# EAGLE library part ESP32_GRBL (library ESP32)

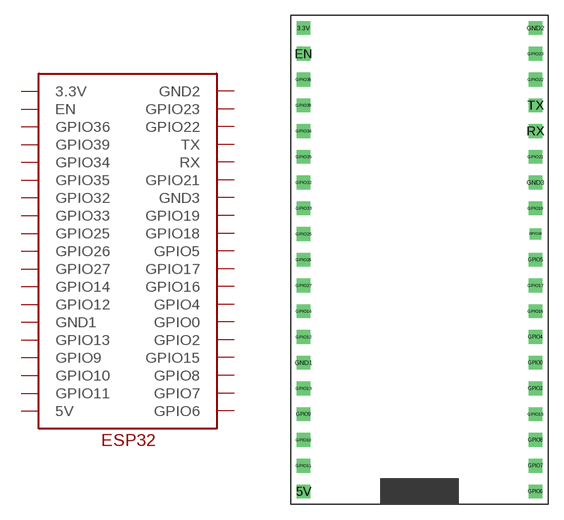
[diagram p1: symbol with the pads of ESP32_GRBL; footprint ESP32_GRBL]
Designator prefix -

## ESP32_GRBL  [ESP32_GRBL]
3.3V  3.3V
5V  5V
EN  EN
GND1  GND1
GND2  GND2
GND3  GND3
GPIO0  GPIO0
GPIO2  GPIO2
GPIO4  GPIO4
GPIO5  GPIO5
GPIO6  GPIO6
GPIO7  GPIO7
GPIO8  GPIO8
GPIO9  GPIO9
GPIO10  GPIO10
GPIO11  GPIO11
GPIO12  GPIO12
GPIO13  GPIO13
GPIO14  GPIO14
GPIO15  GPIO15
GPIO16  GPIO16
GPIO17  GPIO17
GPIO18  GPIO18
GPIO19  GPIO19
GPIO21  GPIO21
GPIO22  GPIO22
GPIO23  GPIO23
GPIO25  GPIO25
GPIO26  GPIO26
GPIO27  GPIO27
GPIO32  GPIO32
GPIO33  GPIO33
GPIO34  GPIO34
GPIO35  GPIO35
GPIO36  GPIO36
GPIO39  GPIO39
RX  RX
TX  TX

## Footprint ESP32_GRBL (pad centres in mm)
drill 0.85 square: 3.3V 1.27,46.99; 5V 1.27,1.27; EN 1.27,44.45; GND1 1.27,13.97; GND2 24.13,46.99; GND3 24.13,31.75; GPIO0 24.13,13.97; GPIO2 24.13,11.43; GPIO4 24.13,16.51; GPIO5 24.13,24.13; GPIO6 24.13,1.27; GPIO7 24.13,3.81; GPIO8 24.13,6.35; GPIO9 1.27,8.89; GPIO10 1.27,6.35; GPIO11 1.27,3.81; GPIO12 1.27,16.51; GPIO13 1.27,11.43; GPIO14 1.27,19.05; GPIO15 24.13,8.89; GPIO16 24.13,19.05; GPIO17 24.13,21.59; GPIO19 24.13,29.21; GPIO21 24.13,34.29; GPIO22 24.13,41.91; GPIO23 24.13,44.45; GPIO25 1.27,26.67; GPIO26 1.27,24.13; GPIO27 1.27,21.59; GPIO32 1.27,31.75; GPIO33 1.27,29.21; GPIO34 1.27,36.83; GPIO35 1.27,34.29; GPIO36 1.27,41.91; GPIO39 1.27,39.37; RX 24.13,36.83; TX 24.13,39.37
drill 0.6 square: GPIO18 24.13,26.67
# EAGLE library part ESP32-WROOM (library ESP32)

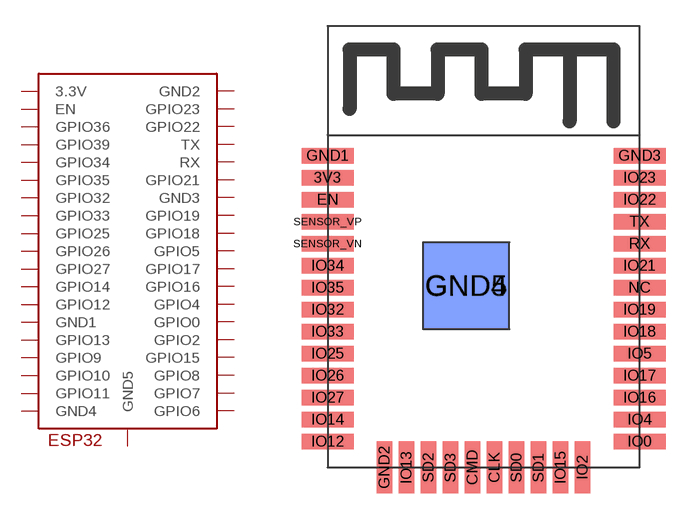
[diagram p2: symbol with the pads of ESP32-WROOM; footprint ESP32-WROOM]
Designator prefix -

## ESP32-WROOM  [ESP32-WROOM]
3V3  3.3V
CLK  GPIO6
CMD  GPIO11
EN  EN
GND1  GND1
GND2  GND2
GND3  GND3
GND4  GND4
GND5  GND5
IO0  GPIO0
IO2  GPIO2
IO4  GPIO4
IO5  GPIO5
IO12  GPIO12
IO13  GPIO13
IO14  GPIO14
IO15  GPIO15
IO16  GPIO16
IO17  GPIO17
IO18  GPIO18
IO19  GPIO19
IO21  GPIO21
IO22  GPIO22
IO23  GPIO23
IO25  GPIO25
IO26  GPIO26
IO27  GPIO27
IO32  GPIO32
IO33  GPIO33
IO34  GPIO34
IO35  GPIO35
RX  RX
SD0  GPIO7
SD1  GPIO8
SD2  GPIO9
SD3  GPIO10
SENSOR_VN  GPIO39
SENSOR_VP  GPIO36
TX  TX

## Footprint ESP32-WROOM (pad centres in mm)
smd 3 x 0.9: 3V3 0,16.74; EN 0,15.47; GND1 0,18.01; GND3 18,18.01; IO0 18,1.5; IO4 18,2.77; IO5 18,6.58; IO12 0,1.5; IO14 0,2.77; IO16 18,4.04; IO17 18,5.31; IO18 18,7.85; IO19 18,9.12; IO21 18,11.66; IO22 18,15.47; IO23 18,16.74; IO25 0,6.58; IO26 0,5.31; IO27 0,4.04; IO32 0,9.12; IO33 0,7.85; IO34 0,11.66; IO35 0,10.39; NC 18,10.39; RX 18,12.93; SENSOR_VN 0,12.93; SENSOR_VP 0,14.2; TX 18,14.2
smd 0.9 x 3: CLK 9.635,0; CMD 8.365,0; GND2 3.285,0; IO2 14.715,0; IO13 4.555,0; IO15 13.445,0; SD0 10.905,0; SD1 12.175,0; SD2 5.825,0; SD3 7.095,0
smd 5 x 5: GND4 8,10.5
smd 5 x 5 bottom: GND5 8,10.5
